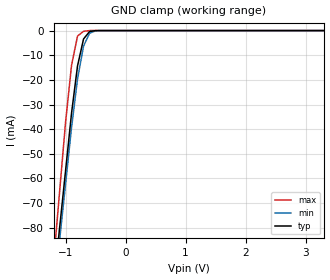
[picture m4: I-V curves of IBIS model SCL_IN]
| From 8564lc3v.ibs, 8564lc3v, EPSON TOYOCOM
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|   Model INPUT
[Model]   SCL_IN
Model_type   Input
Polarity   Non-Inverting
Vinl =   0.9V
Vinh =   2.1V
C_comp   5pF   5pF   5pF
[Temperature Range]   25.00   85.00   -40.00
[Voltage Range]   3.0V   2.7V   3.3V
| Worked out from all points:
|   GND clamp passes 1 mA (typ) near -0.62 V on its own axis
[GND_clamp]
| voltage   I(typ)   I(min)   I(max)
-3.3V     -596.6mA   -590mA     -691.2mA
-1.2V     -103.9mA   -108.2mA   -94.2mA
-1.1V     -80.4mA    -85.3mA    -65.7mA
-1V       -57mA      -62.4mA    -37.3mA
-900mV    -33.5mA    -39.4mA    -14.1mA
-800mV    -14.3mA    -19.6mA    -2.2mA
-700mV    -3.4mA     -6.3mA     -300uA
-600mV    -400uA     -1.1mA     0A
-500mV    0A         -100uA     0A
3.3V      0A         0A         0A
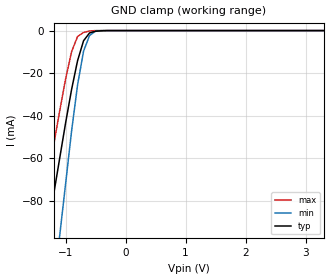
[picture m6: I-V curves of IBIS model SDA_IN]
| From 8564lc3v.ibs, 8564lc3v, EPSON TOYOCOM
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[Model]   SDA_IN
Model_type   Input
Polarity   Non-Inverting
Vinl =   0.9V
Vinh =   2.1V
C_comp   5pF   5pF   5pF
[Temperature Range]   25.00   85.00   -40.00
[Voltage Range]   3.0V   2.7V   3.3V
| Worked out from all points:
|   GND clamp passes 1 mA (typ) near -0.59 V on its own axis
[GND_clamp]
| voltage   I(typ)   I(min)   I(max)
-3.3V     -432.6mA   -643.8mA   -385.8mA
-1.5V     -128.2mA   -196.5mA   -101.6mA
-1.4V     -111.3mA   -171.7mA   -85.8mA
-1.3V     -94.4mA    -146.8mA   -70mA
-1.1V     -60.5mA    -97.1mA    -38.2mA
-1V       -43.6mA    -72.3mA    -22.9mA
-900mV    -27.8mA    -47.4mA    -10mA
-800mV    -14.2mA    -25.6mA    -2.8mA
-700mV    -4.8mA     -9.7mA     -900uA
-600mV    -1.1mA     -2.3mA     -200uA
-400mV    -100uA     0A         0A
3.3V      0A         0A         0A
